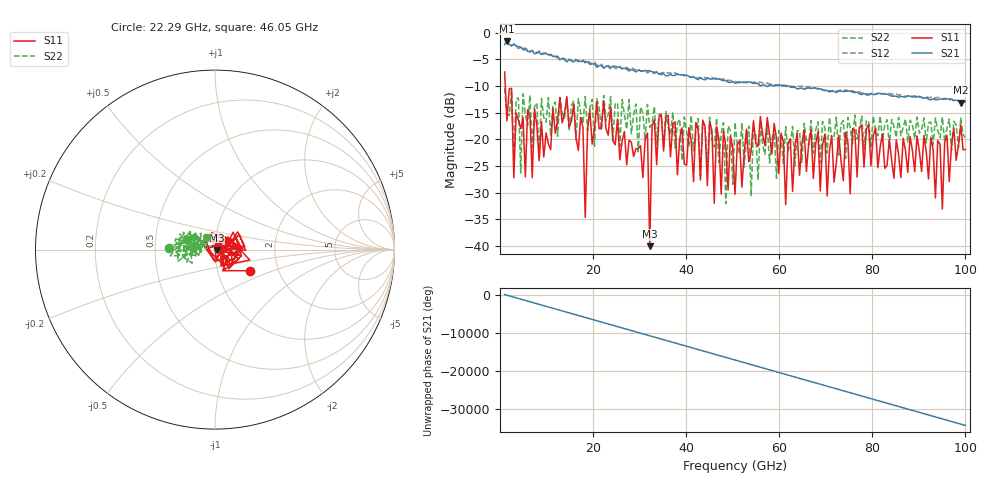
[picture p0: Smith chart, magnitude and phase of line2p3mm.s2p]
!Created with skrf (http://scikit-rf.org).
# GHz S RI R 50.0
!freq ReS11 ImS11 ReS21 ImS21 ReS12 ImS12 ReS22 ImS22
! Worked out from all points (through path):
!   201 points, 1 GHz to 100 GHz, reference 50 ohm
!   highest |S21| = -1.54 dB at 1.495 GHz (marker M1); lowest = -13.1 dB at 99.01 GHz (marker M2)
!   lowest |S11| = -40.1 dB at 32.19 GHz (marker M3), VSWR 1.02, Z = 50.9 - j0.475 ohm
!   |S11| at or under -10 dB: 1.141 GHz to end of sweep
!   |S22| runs from -32.1 to -10.4 dB; largest |S21 - S12| = 0.1
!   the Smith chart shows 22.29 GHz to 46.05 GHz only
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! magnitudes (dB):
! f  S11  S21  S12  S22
! 1 GHz  -7.4  -2.2  -1.5  -10.4
! 1.495 GHz  -16.6  -1.5  -1.5  -15.2
! 17.83 GHz  -17.8  -5.4  -5.2  -17.1
! 18.32 GHz  -34.7  -5.4  -5.7  -12.0
! 19.32 GHz  -14.6  -5.9  -5.6  -14.1
! 31.69 GHz  -18.8  -7.2  -7.6  -13.5
! 32.19 GHz  -40.1  -7.2  -7.3  -17.8
! 32.68 GHz  -17.5  -7.3  -7.5  -17.0
! 34.16 GHz  -15.9  -7.8  -7.7  -15.3
! 44.56 GHz  -28.7  -8.5  -8.6  -25.6
! 45.05 GHz  -16.7  -8.7  -8.6  -15.9
! 46.05 GHz  -32.0  -8.6  -8.6  -21.5
! 48.02 GHz  -18.4  -9.0  -8.7  -16.9
! 48.52 GHz  -21.3  -9.0  -8.9  -32.1
! 50.5 GHz  -30.3  -9.5  -9.2  -16.8
! 53.97 GHz  -22.2  -9.3  -9.4  -30.7
! 55.95 GHz  -15.7  -10.0  -9.3  -17.5
! 67.33 GHz  -27.4  -10.4  -10.4  -22.6
! 83.67 GHz  -20.0  -11.7  -11.4  -21.0
! 95.05 GHz  -33.1  -12.5  -12.4  -15.8
! 99.01 GHz  -17.3  -13.1  -13.0  -16.0
! 100 GHz  -21.9  -13.0  -12.8  -19.7
